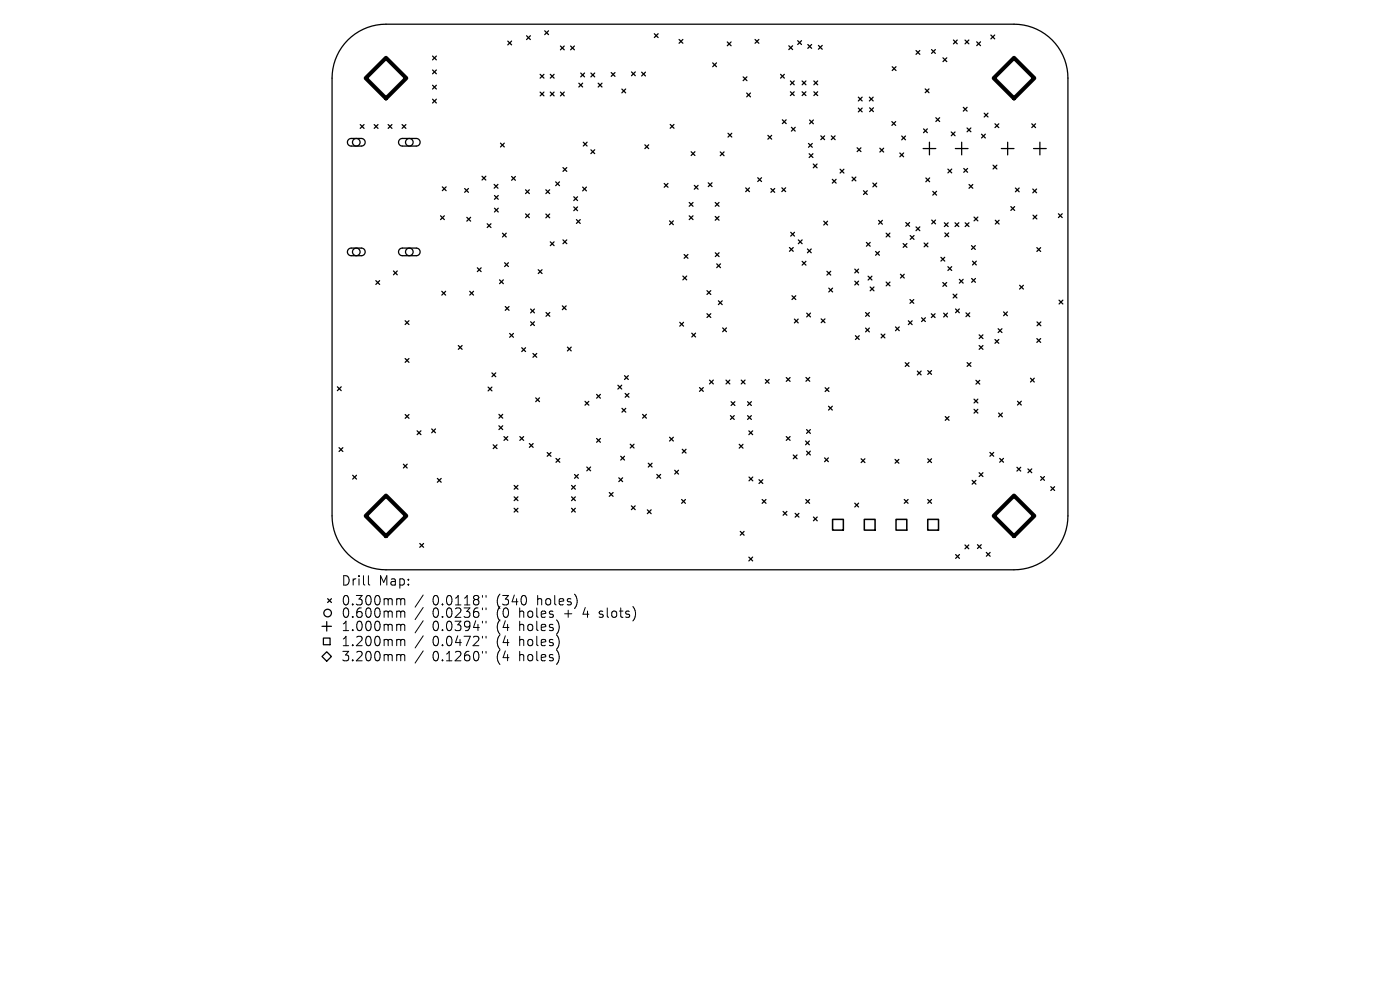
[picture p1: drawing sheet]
<svg xmlns="http://www.w3.org/2000/svg" width="297mm" height="210mm" viewBox="0 0 297 210" stroke-linecap="round" stroke-linejoin="round" font-family="sans-serif">
<defs><g id="words">
<g font-size="2.8">
<text x="72.3" y="124.5">Drill</text>
<text x="80.3" y="124.5">Map:</text>
<text x="72.3" y="128.7">0.300mm</text>
<text x="72.3" y="131.3">0.600mm</text>
<text x="91.8" y="128.7">0.0118&quot;</text>
<text x="91.8" y="131.3">0.0236&quot;</text>
<text x="105.5" y="128.7">(340</text>
<text x="105.5" y="131.3">(0</text>
<text x="110.4" y="131.3">holes</text>
<text x="114.3" y="128.7">holes)</text>
<text x="120.2" y="131.3">+</text>
<text x="124.4" y="131.3">4</text>
<text x="128" y="131.3">slots)</text>
<text x="72.3" y="134.2">1.000mm</text>
<text x="72.3" y="137.4">1.200mm</text>
<text x="91.8" y="134.2">0.0394&quot;</text>
<text x="91.8" y="137.4">0.0472&quot;</text>
<text x="105.5" y="134.2">(4</text>
<text x="105.5" y="137.4">(4</text>
<text x="110.4" y="134.2">holes)</text>
<text x="110.4" y="137.4">holes)</text>
<text x="72.3" y="140.6">3.200mm</text>
<text x="91.8" y="140.6">0.1260&quot;</text>
<text x="105.5" y="140.6">(4</text>
<text x="110.4" y="140.6">holes)</text>
</g>
</g></defs>
<g fill="none" stroke="#000" stroke-width=".27">
<path d="M73.8 8.5a11.4 11.4 0 0 1 8.1-3.4h133.2a11.4 11.4 0 0 1 11.5 11.5v92.8a11.4 11.4 0 0 1-11.5 11.5h-133.2a11.4 11.4 0 0 1-11.5-11.5v-92.8a11.4 11.4 0 0 1 3.4-8.1zM91.8 11.9l.8 .8M91.8 14.9l.8 .8M91.8 18.1l.8 .8M92.6 11.9l-.8 .8M92.6 14.9l-.8 .8M92.6 18.1l-.8 .8M107.7 8.7l.8 .8M108.5 8.7l-.8 .8M111.7 7.6l.8 .8M112.5 7.6l-.8 .8M114.6 15.8l.8 .8"/>
<path d="M114.6 19.5l.8 .8M115.4 15.8l-.8 .8M115.4 19.5l-.8 .8M115.6 6.5l.8 .8M116.4 6.5l-.8 .8M116.7 15.8l.8 .8M116.7 19.5l.8 .8M117.5 15.8l-.8 .8M117.5 19.5l-.8 .8M118.9 9.8l.8 .8M118.9 19.5l.8 .8M119.7 9.8l-.8 .8"/>
<path d="M119.7 19.5l-.8 .8M121 9.8l.9 .8M121.9 9.8l-.9 .8M122.8 17.6l.8 .9M123.2 15.5l.8 .8M123.6 17.6l-.8 .9M124 15.5l-.8 .8M125.4 15.5l.8 .8M126.2 15.5l-.8 .8M126.9 17.7l.8 .8M127.7 17.7l-.8 .8M129.7 15.4l.8 .8"/>
<path d="M130.5 15.4l-.8 .8M131.9 18.9l.8 .8M132.7 18.9l-.8 .8M134 15.3l.8 .8M134.8 15.3l-.8 .8M136.1 15.3l.8 .8M136.9 15.3l-.8 .8M138.8 7.2l.8 .8M139.6 7.2l-.8 .8M144.1 8.4l.8 .8M144.9 8.4l-.8 .8M151.2 13.3l.8 .9"/>
<path d="M152 13.3l-.8 .9M154.3 8.9l.8 .8M155.1 8.9l-.8 .8M157.7 16.3l.8 .8M158.4 19.7l.8 .8M158.5 16.3l-.8 .8M159.2 19.7l-.8 .8M160.2 8.4l.8 .8M161 8.4l-.8 .8M165.6 15.8l.8 .8M166.4 15.8l-.8 .8M167.3 9.7l.8 .8"/>
<path d="M167.7 17.2l.8 .8M167.7 19.5l.8 .8M168.1 9.7l-.8 .8M168.5 17.2l-.8 .8M168.5 19.5l-.8 .8M169.2 8.6l.8 .8M170 8.6l-.8 .8M170.2 17.2l.8 .8M170.2 19.5l.8 .8M171 17.2l-.8 .8M171 19.5l-.8 .8M171.4 9.4l.8 .9"/>
<path d="M172.2 9.4l-.8 .9M172.7 17.2l.8 .8M172.7 19.5l.8 .8M173.5 17.2l-.8 .8M173.5 19.5l-.8 .8M173.6 9.6l.8 .8M174.4 9.6l-.8 .8M189.3 14.2l.8 .8M190.1 14.2l-.8 .8M194.3 10.7l.8 .8M195.1 10.7l-.8 .8M196.3 18.9l.8 .8"/>
<path d="M197.1 18.9l-.8 .8M197.6 10.5l.8 .8M198.4 10.5l-.8 .8M200 12.3l.9 .8M200.9 12.3l-.9 .8M202.3 8.5l.8 .8M203.1 8.5l-.8 .8M204.7 8.5l.8 .8M205.5 8.5l-.8 .8M207.2 8.9l.8 .8M208 8.9l-.8 .8M210.2 7.4l.8 .8"/>
<path d="M211 7.4l-.8 .8M73.9 29.6l.5-.2h2.3a.81 .81 0 0 1 .8 .8 .81 .81 0 0 1-.8 .8h-2.2a.81 .81 0 0 1-.7-.5 .81 .81 0 0 1 .1-.9zM76.4 26.4l.8 .8M77.2 26.4l-.8 .8M79.4 26.4l.8 .8M80.2 26.4l-.8 .8M82.3 26.4l.9 .8M83.2 26.4l-.9 .8M84.8 29.6l.5-.2h3a.81 .81 0 0 1 .8 .8 .81 .81 0 0 1-.8 .8h-2.9a.81 .81 0 0 1-.8-.5 .81 .81 0 0 1 .2-.9zM85.3 26.4l.8 .8M86.1 26.4l-.8 .8M91.8 21l.8 .8"/>
<path d="M92.6 21l-.8 .8M93.8 39.6l.8 .8M94.6 39.6l-.8 .8M98.6 40l.8 .8M99.4 40l-.8 .8M102.3 37.4l.8 .8M103.1 37.4l-.8 .8M104.8 39.1l.8 .8M105.6 39.1l-.8 .8M106.2 30.4l.8 .8M107 30.4l-.8 .8M108.5 37.4l.8 .8"/>
<path d="M109.3 37.4l-.8 .8M117.9 38.6l.8 .8M118.7 38.6l-.8 .8M119.4 35.5l.8 .9M120.2 35.5l-.8 .9M123.6 39.7l.8 .8M123.7 30.2l.8 .8M124.4 39.7l-.8 .8M124.5 30.2l-.8 .8M125.4 31.8l.8 .8M126.2 31.8l-.8 .8M136.8 30.7l.8 .8"/>
<path d="M137.6 30.7l-.8 .8M140.9 38.9l.8 .8M141.7 38.9l-.8 .8M142.2 26.4l.8 .8M143 26.4l-.8 .8M146.6 32.2l.8 .8M147.3 39.3l.8 .8M147.4 32.2l-.8 .8M148.1 39.3l-.8 .8M150.3 38.8l.8 .8M151.1 38.8l-.8 .8M152.8 32.2l.8 .8"/>
<path d="M153.6 32.2l-.8 .8M154.4 28.3l.8 .8M155.2 28.3l-.8 .8M158.2 39.9l.8 .8M159 39.9l-.8 .8M160.7 37.7l.9 .8M161.6 37.7l-.9 .8M162.9 28.7l.8 .8M163.5 40l.8 .8M163.7 28.7l-.8 .8M164.3 40l-.8 .8M165.9 39.8l.8 .8"/>
<path d="M166 25.4l.8 .8M166.7 39.8l-.8 .8M166.8 25.4l-.8 .8M167.9 27l.8 .8M168.7 27l-.8 .8M171.5 30.4l.8 .8M171.7 32.6l.8 .8M171.7 25.5l.9 .8M172.3 30.4l-.8 .8M172.5 32.6l-.8 .8M172.5 34.8l.8 .8M172.6 25.5l-.9 .8"/>
<path d="M173.3 34.8l-.8 .8M174.1 28.8l.8 .8M174.9 28.8l-.8 .8M176.4 28.8l.8 .8M176.6 38l.8 .8M177.2 28.8l-.8 .8M177.4 38l-.8 .8M178.2 35.9l.8 .8M179 35.9l-.8 .8M180.8 37.6l.8 .8M181.6 37.6l-.8 .8M181.8 31.4l.8 .8"/>
<path d="M182.1 20.6l.8 .8M182.1 22.9l.8 .8M182.6 31.4l-.8 .8M182.9 20.6l-.8 .8M182.9 22.9l-.8 .8M184.4 20.6l.8 .8M184.5 22.9l.8 .8M185.2 38.8l.8 .8M185.2 20.6l-.8 .8M185.3 22.9l-.8 .8M186 38.8l-.8 .8M186.7 31.4l.8 .9"/>
<path d="M187.5 31.4l-.8 .9M189.2 25.8l.8 .8M190 25.8l-.8 .8M190.9 32.5l.8 .8M191.3 28.9l.8 .8M191.7 32.5l-.8 .8M192.1 28.9l-.8 .8M195.8 31.5h2.7M195.9 27.3l.8 .8M196.4 37.7l.8 .9M196.7 27.3l-.8 .8M197.2 30.2v2.7"/>
<path d="M197.2 37.7l-.8 .9M198.5 25l.8 .8M199.3 25l-.8 .8M201.1 35.9l.8 .8M201.8 28l.8 .8M201.9 35.9l-.8 .8M202.6 28l-.8 .8M202.7 31.5h2.7M204 30.2v2.7M204.4 22.8l.8 .8M204.5 35.7l.8 .8M205.2 27.2l.8 .8"/>
<path d="M205.2 22.8l-.8 .8M205.3 35.7l-.8 .8M205.6 39.1l.8 .8M206 27.2l-.8 .8M206.4 39.1l-.8 .8M208.2 28.5l.8 .8M208.8 24l.8 .8M209 28.5l-.8 .8M209.6 24l-.8 .8M210.7 35l.8 .8M211.1 26.3l.8 .8M211.5 35l-.8 .8"/>
<path d="M211.9 26.3l-.8 .8M212.4 31.5h2.7M213.8 30.2v2.7M215.4 39.9l.8 .8M216.2 39.9l-.8 .8M218.9 26.3l.8 .8M219.3 31.5h2.7M219.7 26.3l-.8 .8M220.6 30.2v2.7M73.9 52.9l.5-.3h2.3a.81 .81 0 0 1 .8 .8 .81 .81 0 0 1-.8 .8h-2.2a.81 .81 0 0 1-.7-.5 .81 .81 0 0 1 .1-.8zM79.7 59.5l.8 .8M80.5 59.5l-.8 .8"/>
<path d="M83.5 57.5l.8 .8M84.3 57.5l-.8 .8M84.8 52.9l.5-.3h3a.81 .81 0 0 1 .8 .8 .81 .81 0 0 1-.8 .8h-2.9a.81 .81 0 0 1-.8-.5 .81 .81 0 0 1 .2-.8zM93.5 45.8l.8 .8M94.3 45.8l-.8 .8M99 46.1l.8 .8M99.8 46.1l-.8 .8M101.3 56.8l.8 .8M102.1 56.8l-.8 .8M103.4 47.5l.8 .8M104.2 47.5l-.8 .8M104.9 41.5l.8 .8"/>
<path d="M104.9 44.2l.8 .8M105.7 41.5l-.8 .8M105.7 44.2l-.8 .8M106 59.4l.8 .8M106.6 49.5l.8 .8M106.8 59.4l-.8 .8M107.1 55.7l.8 .8M107.4 49.5l-.8 .8M107.9 55.7l-.8 .8M111.5 40.3l.8 .8M111.5 45.4l.8 .8M112.3 40.3l-.8 .8"/>
<path d="M112.3 45.4l-.8 .8M114.2 57.2l.8 .8M115 57.2l-.8 .8M115.8 40.3l.8 .8M115.8 45.4l.8 .8M116.6 40.3l-.8 .8M116.6 45.4l-.8 .8M116.7 51.3l.8 .8M117.5 51.3l-.8 .8M119.4 50.9l.8 .8M120.2 50.9l-.8 .8M121.7 41.7l.8 .8"/>
<path d="M121.7 43.9l.8 .8M122.3 46.6l.8 .8M122.5 41.7l-.8 .8M122.5 43.9l-.8 .8M123.1 46.6l-.8 .8M142 46.9l.8 .8M142.8 46.9l-.8 .8M144.9 58.6l.8 .8M145.1 54l.8 .8M145.7 58.6l-.8 .8M145.9 54l-.8 .8M146.2 43l.8 .8"/>
<path d="M146.2 45.8l.8 .8M147 43l-.8 .8M147 45.8l-.8 .8M151.7 43l.8 .8M151.7 45.9l.8 .8M151.7 53.6l.9 .8M152 56l.9 .8M152.5 43l-.8 .8M152.5 45.9l-.8 .8M152.6 53.6l-.9 .8M152.9 56l-.9 .8M167.5 52.5l.8 .8"/>
<path d="M167.7 49.3l.9 .8M168.3 52.5l-.8 .8M168.6 49.3l-.9 .8M169.4 50.9l.8 .8M170.2 50.9l-.8 .8M170.2 55.4l.8 .8M171 55.4l-.8 .8M171.3 52.8l.8 .8M172.1 52.8l-.8 .8M174.8 46.9l.8 .8M175.4 57.5l.8 .9M175.6 46.9l-.8 .8"/>
<path d="M176.2 57.5l-.8 .9M181.3 57.1l.8 .8M181.3 59.6l.8 .8M182.1 57.1l-.8 .8M182.1 59.6l-.8 .8M183.2 40.5l.8 .8M183.8 51.4l.8 .8M184 40.5l-.8 .8M184.2 58.6l.8 .8M184.6 51.4l-.8 .8M185 58.6l-.8 .8M185.8 53.3l.8 .8"/>
<path d="M186.4 46.7l.8 .9M186.6 53.3l-.8 .8M187.2 46.7l-.8 .9M188 49.5l.8 .8M188 59.8l.8 .8M188.8 49.5l-.8 .8M188.8 59.8l-.8 .8M191 58.2l.8 .8M191.6 51.7l.8 .8M191.8 58.2l-.8 .8M192.2 47.2l.8 .8M192.4 51.7l-.8 .8"/>
<path d="M193 47.2l-.8 .8M193.1 50l.8 .8M193.9 50l-.8 .8M194.3 48.1l.8 .8M195.1 48.1l-.8 .8M196 51.6l.9 .8M196.9 51.6l-.9 .8M197.7 46.7l.8 .8M197.9 40.6l.8 .8M198.5 46.7l-.8 .8M198.7 40.6l-.8 .8M199.6 54.6l.8 .8"/>
<path d="M200 59.9l.8 .8M200.3 47.3l.8 .8M200.4 54.6l-.8 .8M200.4 49.4l.9 .8M200.8 59.9l-.8 .8M201.1 56.6l.8 .8M201.1 47.3l-.8 .8M201.3 49.4l-.9 .8M201.9 56.6l-.8 .8M202.6 47.3l.8 .8M203.4 47.3l-.8 .8M203.5 59.3l.8 .8"/>
<path d="M204.3 59.3l-.8 .8M204.8 47.3l.8 .8M205.6 47.3l-.8 .8M206.1 52.1l.8 .8M206.1 59.1l.8 .8M206.3 55.4l.8 .8M206.6 46l.8 .9M206.9 52.1l-.8 .8M206.9 59.1l-.8 .8M207.1 55.4l-.8 .8M207.4 46l-.8 .9M211.1 46.7l.9 .8"/>
<path d="M212 46.7l-.9 .8M214.4 43.8l.9 .8M215.3 43.8l-.9 .8M219.1 40.1l.8 .8M219.2 45.6l.8 .8M219.9 40.1l-.8 .8M220 45.6l-.8 .8M220 52.5l.8 .8M220.8 52.5l-.8 .8M224.5 45.3l.8 .9M225.3 45.3l-.8 .9M86 68l.8 .8"/>
<path d="M86 76.1l.8 .8M86.8 68l-.8 .8M86.8 76.1l-.8 .8M93.7 61.8l.8 .8M94.5 61.8l-.8 .8M97.2 73.3l.8 .8M98 73.3l-.8 .8M99.7 61.8l.8 .8M100.5 61.8l-.8 .8M104.4 79.1l.8 .8M105.2 79.1l-.8 .8M107.2 65l.8 .8"/>
<path d="M108 65l-.8 .8M108.1 70.7l.8 .8M108.9 70.7l-.8 .8M110.7 73.8l.8 .8M111.5 73.8l-.8 .8M112.6 65.6l.8 .8M112.6 68.3l.8 .8M113.1 75l.8 .8M113.4 65.6l-.8 .8M113.4 68.3l-.8 .8M113.9 75l-.8 .8M115.8 66.3l.8 .8"/>
<path d="M116.6 66.3l-.8 .8M119.3 64.9l.8 .8M120.1 64.9l-.8 .8M120.4 73.6l.8 .8M121.2 73.6l-.8 .8M132.5 79.7l.8 .8M133.3 79.7l-.8 .8M144.2 68.4l.8 .8M145 68.4l-.8 .8M146.8 70.7l.8 .8M147.6 70.7l-.8 .8M150 61.7l.8 .8"/>
<path d="M150 66.5l.8 .8M150.8 61.7l-.8 .8M150.8 66.5l-.8 .8M152.4 63.8l.8 .8M153.2 63.8l-.8 .8M153.3 69.6l.8 .8M154.1 69.6l-.8 .8M168 62.7l.8 .8M168.5 67.7l.8 .8M168.8 62.7l-.8 .8M169.3 67.7l-.8 .8M171.1 66.4l.8 .8"/>
<path d="M171.9 66.4l-.8 .8M174.2 67.6l.8 .9M175 67.6l-.8 .9M175.8 61.1l.8 .8M176.6 61.1l-.8 .8M181.5 71.2l.8 .8M182.3 71.2l-.8 .8M183.6 66.3l.8 .8M183.6 69.6l.8 .8M184.4 66.3l-.8 .8M184.4 69.6l-.8 .8M184.6 60.9l.8 .8"/>
<path d="M185.4 60.9l-.8 .8M186.9 70.9l.8 .8M187.7 70.9l-.8 .8M190 69.3l.8 .9M190.8 69.3l-.8 .9M192 76.9l.8 .8M192.7 68.1l.8 .8M192.8 76.9l-.8 .8M193 63.5l.9 .8M193.5 68.1l-.8 .8M193.9 63.5l-.9 .8M194.6 78.7l.8 .8"/>
<path d="M195.4 78.7l-.8 .8M195.5 67.4l.8 .8M196.3 67.4l-.8 .8M196.8 78.6l.8 .8M197.6 66.6l.8 .8M197.6 78.6l-.8 .8M198.4 66.6l-.8 .8M200.2 66.4l.8 .8M201 66.4l-.8 .8M202.2 62.4l.8 .8M202.7 65.5l.8 .8M203 62.4l-.8 .8"/>
<path d="M203.5 65.5l-.8 .8M204.9 66.4l.8 .8M205.2 76.9l.8 .8M205.7 66.4l-.8 .8M206 76.9l-.8 .8M207.7 71l.8 .8M207.7 73.3l.8 .8M208.5 71l-.8 .8M208.5 73.3l-.8 .8M211.1 72l.8 .8M211.8 69.7l.8 .8M211.9 72l-.8 .8"/>
<path d="M212.6 69.7l-.8 .8M212.9 66.2l.8 .8M213.7 66.2l-.8 .8M216.3 60.5l.8 .8M217.1 60.5l-.8 .8M220 71.8l.8 .8M220 68.3l.8 .8M220.8 71.8l-.8 .8M220.8 68.3l-.8 .8M224.7 63.7l.8 .8M225.5 63.7l-.8 .8M71.6 82.1l.8 .8"/>
<path d="M71.9 95l.8 .8M72.4 82.1l-.8 .8M72.7 95l-.8 .8M85.6 98.5l.8 .8M86 87.9l.8 .8M86.4 98.5l-.8 .8M86.8 87.9l-.8 .8M88.5 91.4l.8 .8M89.3 91.4l-.8 .8M91.6 91l.8 .8M92.4 91l-.8 .8M103.6 82.1l.8 .8"/>
<path d="M104.4 82.1l-.8 .8M104.6 94.4l.8 .8M105.4 94.4l-.8 .8M105.8 87.9l.8 .8M105.8 90.3l.8 .8M106.6 87.9l-.8 .8M106.6 90.3l-.8 .8M106.9 92.6l.8 .8M107.7 92.6l-.8 .8M110.3 92.6l.8 .8M111.1 92.6l-.8 .8M112.3 94.1l.8 .8"/>
<path d="M113.1 94.1l-.8 .8M113.6 84.4l.9 .8M114.5 84.4l-.9 .8M116.1 96l.8 .8M116.9 96l-.8 .8M118 97.3l.8 .8M118.8 97.3l-.8 .8M124.1 85.1l.8 .8M124.5 99.1l.8 .8M124.9 85.1l-.8 .8M125.3 99.1l-.8 .8M126.6 83.7l.8 .8"/>
<path d="M126.6 93l.8 .8M127.4 83.7l-.8 .8M127.4 93l-.8 .8M131.1 81.7l.8 .8M131.7 96.8l.8 .8M131.9 81.7l-.8 .8M131.9 86.6l.9 .8M132.5 96.8l-.8 .8M132.6 83.5l.8 .8M132.8 86.6l-.9 .8M133.4 83.5l-.8 .8M133.7 94.2l.8 .8"/>
<path d="M134.5 94.2l-.8 .8M136.3 87.9l.8 .8M137.1 87.9l-.8 .8M137.5 98.3l.8 .8M138.3 98.3l-.8 .8M142 92.7l.8 .9M142.8 92.7l-.8 .9M143.1 99.8l.8 .8M143.9 99.8l-.8 .8M144.7 95.3l.8 .8M145.5 95.3l-.8 .8M148.4 82.2l.8 .8"/>
<path d="M149.2 82.2l-.8 .8M150.5 80.6l.8 .8M151.3 80.6l-.8 .8M154 80.6l.8 .8M154.8 80.6l-.8 .8M155 88.2l.8 .8M155.1 85.2l.8 .8M155.8 88.2l-.8 .8M155.9 85.2l-.8 .8M156.8 94.3l.8 .8M157.2 80.6l.9 .8M157.6 94.3l-.8 .8"/>
<path d="M158.1 80.6l-.9 .8M158.6 85.2l.8 .8M158.6 88.2l.8 .8M158.9 91.4l.8 .8M159.4 85.2l-.8 .8M159.4 88.2l-.8 .8M159.7 91.4l-.8 .8M162.4 80.5l.8 .8M163.2 80.5l-.8 .8M166.8 80.1l.8 .8M166.8 92.6l.8 .8M167.6 80.1l-.8 .8"/>
<path d="M167.6 92.6l-.8 .8M168.3 96.5l.8 .8M169.1 96.5l-.8 .8M170.9 93.6l.8 .8M171 80.1l.8 .8M171.1 91.1l.8 .8M171.1 95.7l.8 .8M171.7 93.6l-.8 .8M171.8 80.1l-.8 .8M171.9 91.1l-.8 .8M171.9 95.7l-.8 .8M174.9 97.1l.8 .8"/>
<path d="M175 82.2l.9 .9M175.7 97.1l-.8 .8M175.8 86.2l.8 .8M175.9 82.2l-.9 .9M176.6 86.2l-.8 .8M182.7 97.3l.8 .8M183.5 97.3l-.8 .8M189.9 97.5l.8 .8M190.7 97.5l-.8 .8M196.8 97.3l.8 .8M197.6 97.3l-.8 .8M200.5 88.4l.8 .8"/>
<path d="M201.3 88.4l-.8 .8M206.6 84.7l.8 .8M206.6 86.8l.8 .8M207 80.7l.8 .8M207.4 84.7l-.8 .8M207.4 86.8l-.8 .8M207.8 80.7l-.8 .8M210 96l.8 .8M210.8 96l-.8 .8M211.8 87.6l.8 .8M212.1 97.2l.8 .8M212.6 87.6l-.8 .8"/>
<path d="M212.9 97.2l-.8 .8M215.7 99.1l.8 .8M215.9 85.1l.8 .8M216.5 99.1l-.8 .8M216.7 85.1l-.8 .8M218.1 99.5l.8 .8M218.6 80.2l.8 .8M218.9 99.5l-.8 .8M219.4 80.2l-.8 .8M74.8 100.8l.8 .8M75.6 100.8l-.8 .8M89.1 115.3l.8 .8"/>
<path d="M89.9 115.3l-.8 .8M92.8 101.5l.8 .8M93.6 101.5l-.8 .8M109.1 103l.8 .8M109.1 105.4l.8 .8M109.1 107.8l.8 .8M109.9 103l-.8 .8M109.9 105.4l-.8 .8M109.9 107.8l-.8 .8M121.2 103l.9 .8M121.2 105.4l.9 .8M121.2 107.8l.9 .8"/>
<path d="M121.9 100.7l.8 .8M122.1 103l-.9 .8M122.1 105.4l-.9 .8M122.1 107.8l-.9 .8M122.7 100.7l-.8 .8M129.3 104.5l.8 .8M130.1 104.5l-.8 .8M131.3 101.4l.8 .8M132.1 101.4l-.8 .8M133.9 107.3l.9 .8M134.8 107.3l-.9 .8M137.3 108.2l.8 .8"/>
<path d="M138.1 108.2l-.8 .8M139.3 100.6l.9 .8M140.2 100.6l-.9 .8M144.6 106l.8 .8M145.4 106l-.8 .8M157 112.7l.9 .8M157.9 112.7l-.9 .8M158.9 118.2l.8 .8M158.9 101.2l.8 .8M159.7 118.2l-.8 .8M159.7 101.2l-.8 .8M161 101.8l.8 .8"/>
<path d="M161.7 106l.8 .8M161.8 101.8l-.8 .8M162.5 106l-.8 .8M166.1 108.5l.8 .8M166.9 108.5l-.8 .8M168.7 108.9l.8 .8M169.5 108.9l-.8 .8M170.9 106l.8 .8M171.7 106l-.8 .8M172.6 109.7l.8 .8M173.4 109.7l-.8 .8M181.3 106.7l.8 .8"/>
<path d="M182.1 106.7l-.8 .8M191.8 106l.8 .8M192.6 106l-.8 .8M196.8 106l.8 .8M197.6 106l-.8 .8M202.7 117.6l.8 .8M203.5 117.6l-.8 .8M204.7 115.6l.8 .8M205.5 115.6l-.8 .8M206.2 101.9l.8 .8M207 101.9l-.8 .8M207.4 115.5l.8 .9"/>
<path d="M207.7 100.3l.8 .8M208.2 115.5l-.8 .9M208.5 100.3l-.8 .8M209.2 117.2l.9 .8M210.1 117.2l-.9 .8M220.8 101.1l.8 .8M221.6 101.1l-.8 .8M222.9 103.2l.8 .8M223.7 103.2l-.8 .8M68.3 139.3l1-1 1 1-1 1zM68.3 132.9h2M68.6 135.4h1.4v1.4h-1.4z"/>
<path d="M69.3 131.9v2M69.5 127l.8 .8M70.3 127l-.8 .8"/>
<circle cx="75.6" cy="30.2" r=".81"/>
<circle cx="86.8" cy="30.2" r=".81"/>
<circle cx="75.6" cy="53.4" r=".81"/>
<circle cx="86.8" cy="53.4" r=".81"/>
<circle cx="69.5" cy="130" r=".81"/>
</g>
<path d="M176.6 110.2h2.3v2.3h-2.3zM183.4 110.2h2.2v2.3h-2.2zM190.1 110.2h2.3v2.3h-2.3zM196.8 110.2h2.3v2.3h-2.3z" fill="none" stroke="#000" stroke-width=".32"/>
<path d="M81.9 12.3l4.3 4.3-4.3 4.3-4.3-4.3zM210.8 16.6l4.3-4.3 4.3 4.3-4.3 4.3zM77.6 109.4l4.3-4.3 4.3 4.3-4.3 4.3zM210.8 109.4l4.3-4.3 4.3 4.3-4.3 4.3z" fill="none" stroke="#000" stroke-width=".86"/>
<g fill="none" stroke="#000" stroke-width=".21">
<path d="M78.2 122.1v1.7l.2 .3M84.4 127l.5 .1 .1 .2M84.4 129.6h.3l.3 .3M84.4 132.4h.3l.3 .3M84.4 135.6h.3l.3 .3M84.4 138.8h.3l.3 .3M85 127.3l.3-.3 .5 .1 .1 1.2M85 127.3v1M85 129.9v1.1M85 132.7v1.1M85 135.9v1.1M85 139.1v1.1"/>
<path d="M85 129.9l.3-.3 .5 .1 .1 1.3M85 132.7l.3-.3 .5 .1 .1 1.3M85 135.9l.3-.3 .5 .1 .1 1.3M85 139.1l.3-.3 .5 .1 .1 1.3M89.8 126.2l-1.7 2.6M89.8 128.9l-1.7 2.5M89.8 131.7l-1.7 2.6M89.8 134.9l-1.7 2.6M89.8 138.1l-1.7 2.6M102.3 126.3v.4M102.3 129v.3M102.3 131.8v.4"/>
<path d="M102.3 135v.4M102.3 138.2v.4M103.1 126.3v.4M103.1 129v.3M103.1 131.8v.4M103.1 135v.4M103.1 138.2v.4M127.1 130.9l.2 .1M127.2 129.7v.5"/>
</g>
<use href="#words"/>
</svg>
